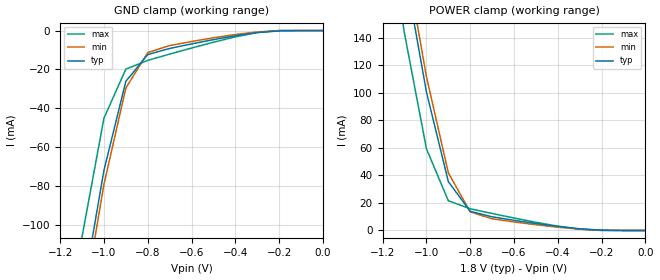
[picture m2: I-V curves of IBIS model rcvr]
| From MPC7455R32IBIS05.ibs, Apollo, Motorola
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| *   rcvr  Model   *
[Model]   rcvr
Model_type   Input
Polarity   Non-Inverting
Vinl =   0.63V
Vinh =   1.17V
|   typ   min   max
C_comp   2.995206e-12   2.721714e-12   3.190203e-12
|   typ   min   max
[Voltage range]   1.8V   1.6V   2.0V
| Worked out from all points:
|   GND clamp passes 1 mA (typ) near -0.30 V on its own axis
|   POWER clamp passes 1 mA (typ) near -0.28 V on its own axis
|   Voltage(V)   I(typ)   I(min)   I(max)
[GND_clamp]
-1.8V     -692.2mA   -700.9mA   -672.6mA
-1.1V     -137.6mA   -145.8mA   -106.1mA
-1V       -71.91mA   -79.16mA   -45.08mA
-900mV    -26.15mA   -29.57mA   -19.84mA
-800mV    -12.35mA   -11.32mA   -15.34mA
-700mV    -9.208mA   -7.735mA   -12.11mA
-500mV    -4.669mA   -3.719mA   -5.996mA
-300mV    -1.03mA    -697.1uA   -1.016mA
-200mV    -155uA     0A         0A
0V        0A         0A         0A
[POWER_clamp]
-1.8V     934mA      946.7mA    899.1mA
-1.2V     288.7mA    301.3mA    242mA
-1.1V     189.8mA    202.2mA    142.8mA
-1V       100.5mA    111.6mA    59.25mA
-900mV    35.41mA    41.78mA    21.54mA
-800mV    13.89mA    13.47mA    15.75mA
-700mV    9.911mA    8.501mA    12.32mA
-500mV    5.051mA    4.177mA    5.943mA
-300mV    1.219mA    960.4uA    937uA
-200mV    234.6uA    184.6uA    0A
0V        0A         0A         0A
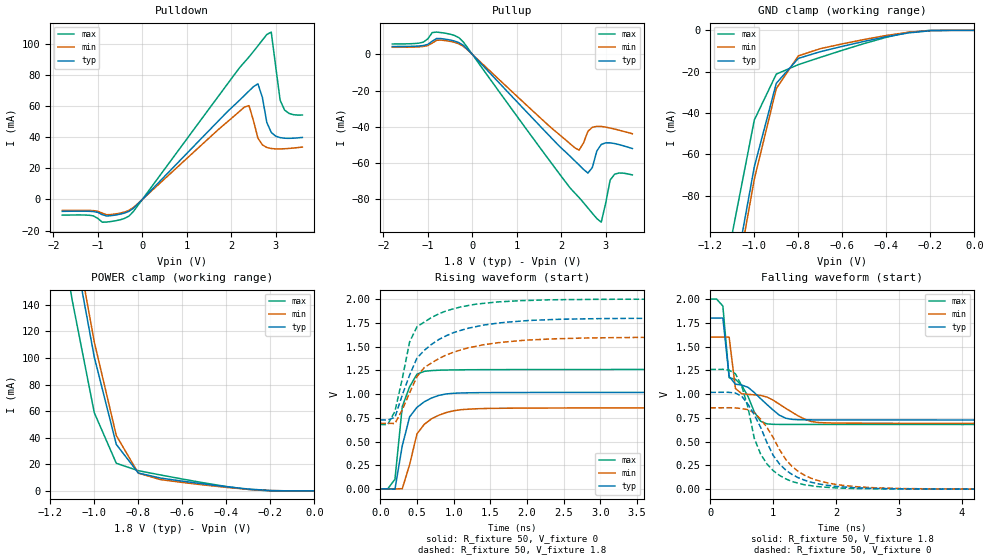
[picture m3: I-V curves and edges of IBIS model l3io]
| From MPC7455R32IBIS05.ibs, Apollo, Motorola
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| *   l3io Model   *
[Model]   l3io
Model_type   I/O
Polarity   Non-Inverting
Vinl = 0.63V
Vinh = 1.17V
Vmeas = 0.9V
Cref = 0
Rref = 50
Vref = 0.9V
|   typ   min   max
C_comp   5.739587e-12   4.578213e-12   6.079571e-12
|   typ   min   max
[Voltage range]   1.8V   1.6V   2.0V
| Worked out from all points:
|   slope of the pulldown table from 0 to 0.27 V, typ, clamps not added: 33.8 ohm
|   slope of the pullup table from 0 to 0.27 V, typ, clamps not added: 38.3 ohm
|   GND clamp passes 1 mA (typ) near -0.28 V on its own axis
|   POWER clamp passes 1 mA (typ) near -0.26 V on its own axis
|   falling waveform, R_fixture 50, V_fixture 1.8: 20-80 % time 583ps typ, 814ps min, 394ps max; typ from 1.8 V to 0.727 V
|   rising waveform, R_fixture 50, V_fixture 0: 20-80 % time 210ps typ, 240ps min, 147ps max; typ from 0.001 V to 1.02 V
|   falling waveform, R_fixture 50, V_fixture 0: 20-80 % time 526ps typ, 576ps min, 385ps max; typ from 1.02 V to 0.001 V
|   rising waveform, R_fixture 50, V_fixture 1.8: 20-80 % time 547ps typ, 602ps min, 319ps max; typ from 0.727 V to 1.8 V
[Pulldown]
|   Voltage   I(typ)   I(min)   I(max)
-1.8V     -7.641mA   -7.07mA    -10.08mA
-900mV    -9.796mA   -8.804mA   -14.61mA
-300mV    -7.639mA   -6.985mA   -10.68mA
2.3V      66.93mA    59.43mA    88.35mA
2.4V      69.74mA    60.31mA    91.62mA
2.6V      74.34mA    39.43mA    98.76mA
2.7V      65.65mA    35.11mA    102.4mA
2.8V      49.57mA    33.44mA    106mA
2.9V      43.11mA    32.75mA    107.6mA
3.1V      39.74mA    32.49mA    63.77mA
3.3V      39.29mA    32.81mA    55.3mA
3.6V      39.87mA    33.67mA    54.29mA
[GND_clamp]
-1.8V     -625.3mA   -632.6mA   -610.7mA
-1.1V     -125.1mA   -132mA     -98.25mA
-1V       -66.1mA    -72.13mA   -43.45mA
-900mV    -25.64mA   -28.19mA   -21.2mA
-800mV    -13.59mA   -12.39mA   -16.62mA
-700mV    -10.34mA   -8.877mA   -13.09mA
-600mV    -7.762mA   -6.559mA   -9.662mA
-400mV    -3.09mA    -2.485mA   -3.371mA
-300mV    -1.244mA   -940.2uA   -993.7uA
-200mV    -205.1uA   -143.9uA   0A
0V        0A         0A         0A
[Pullup]
-1.8V     4.335mA    3.904mA    5.72mA
-1.1V     4.864mA    4.363mA    6.749mA
-800mV    8.763mA    7.798mA    12.28mA
-300mV    6.436mA    5.775mA    9.187mA
2.3V      -58.66mA   -51.48mA   -76.42mA
2.4V      -61.09mA   -52.94mA   -79.02mA
2.6V      -65.55mA   -42.54mA   -84.82mA
2.7V      -62.49mA   -40.27mA   -87.75mA
2.9V      -49.76mA   -39.82mA   -92.68mA
3.1V      -48.87mA   -40.69mA   -69.43mA
3.3V      -49.83mA   -41.88mA   -65.51mA
3.6V      -52.02mA   -43.84mA   -66.57mA
[POWER_clamp]
-1.8V     942.3mA    955.5mA    906.9mA
-1.2V     290.7mA    303.7mA    243.4mA
-1.1V     190.9mA    203.6mA    143.2mA
-1V       100.6mA    112.1mA    58.85mA
-900mV    35.02mA    41.7mA     20.82mA
-800mV    13.5mA     13.36mA    15.24mA
-700mV    9.714mA    8.549mA    12.03mA
-500mV    5.167mA    4.444mA    6.022mA
-300mV    1.42mA     1.194mA    1.111mA
-200mV    314.6uA    266.7uA    0A
0V        0A         0A         0A
|   typ   min   max
[Ramp]
dV/dt_r   0.61068/1.72643e-10   0.51340/2.21908e-10   0.75576/1.50376e-10
dV/dt_f   0.64362/5.50366e-10   0.54500/7.93326e-10   0.79212/4.13710e-10
[Falling Waveform]
R_fixture = 50
V_fixture = 1.8
V_fixture_min = 1.6
V_fixture_max = 2.0
| time   V(typ)   V(min)   V(max)
0s        1.8V       1.6V       2V
200ps     1.801V     1.6V       1.927V
300ps     1.185V     1.6V       1.173V
400ps     1.105V     1.06V      1.156V
800ps     953.1mV    986.4mV    715.4mV
900ps     891.6mV    969.5mV    687.1mV
1.2ns     746.8mV    850.6mV    681.4mV
1.6ns     729.6mV    713.6mV    681.1mV
1.9ns     728.9mV    697mV      681.1mV
19.7ns    727.2mV    691.6mV    679.7mV
[Rising Waveform]
R_fixture = 50
V_fixture = 0
V_fixture_min = 0
V_fixture_max = 0
| time   V(typ)   V(min)   V(max)
0s        785.7uV    646.4uV    681.4uV
100ps     768.2uV    656.3uV    818uV
200ps     -1.583mV   777.5uV    102mV
300ps     455.9mV    3.77mV     868.7mV
400ps     760mV      256.9mV    1.077V
500ps     860mV      580.7mV    1.209V
700ps     958.7mV    739.9mV    1.247V
1.1ns     1.011V     835.5mV    1.255V
1.7ns     1.016V     850.6mV    1.257V
19.7ns    1.019V     856.3mV    1.26V
[Falling Waveform]
R_fixture = 50
V_fixture = 0
V_fixture_min = 0
V_fixture_max = 0
| time   V(typ)   V(min)   V(max)
0s        1.019V     856.3mV    1.26V
400ps     1.011V     855mV      1.214V
500ps     978.9mV    848.6mV    1.087V
700ps     782.4mV    803.7mV    535mV
900ps     492.3mV    651.6mV    266.8mV
1.1ns     265.8mV    417.7mV    146mV
1.3ns     155.5mV    239.6mV    80.93mV
1.7ns     59.35mV    93.52mV    28.46mV
3.5ns     2.596mV    3.98mV     2.137mV
19.7ns    739.6uV    604.6uV    709.7uV
[Rising Waveform]
R_fixture = 50
V_fixture = 1.8
V_fixture_min = 1.6
V_fixture_max = 2.0
| time   V(typ)   V(min)   V(max)
0s        727.2mV    691.6mV    679.7mV
100ps     726.6mV    691.6mV    677.1mV
200ps     754.6mV    689.4mV    817.8mV
400ps     1.2V       1.013V     1.549V
500ps     1.379V     1.183V     1.708V
600ps     1.46V      1.279V     1.758V
900ps     1.614V     1.411V     1.876V
1.6ns     1.746V     1.54V      1.97V
4ns       1.798V     1.598V     1.999V
19.7ns    1.8V       1.6V       2V
